VERSION 5.7 ;
BUSBITCHARS "[]" ;
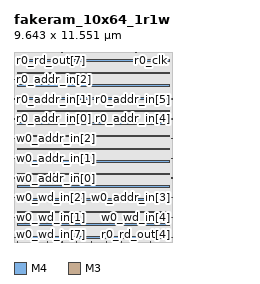
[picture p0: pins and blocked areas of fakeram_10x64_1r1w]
MACRO fakeram_10x64_1r1w
  FOREIGN fakeram_10x64_1r1w 0 0 ;
  SYMMETRY X Y R90 ;
  SIZE 9.643 BY 11.551 ;
  CLASS BLOCK ;
  PIN w0_wd_in[0]
    DIRECTION INPUT ;
    USE SIGNAL ;
    SHAPE ABUTMENT ;
    PORT
      LAYER M4 ;
      RECT 0.000 0.276 0.072 0.300 ;
    END
  END w0_wd_in[0]
  PIN w0_wd_in[1]
    DIRECTION INPUT ;
    USE SIGNAL ;
    SHAPE ABUTMENT ;
    PORT
      LAYER M4 ;
      RECT 0.000 1.476 0.072 1.500 ;
    END
  END w0_wd_in[1]
  PIN w0_wd_in[2]
    DIRECTION INPUT ;
    USE SIGNAL ;
    SHAPE ABUTMENT ;
    PORT
      LAYER M4 ;
      RECT 0.000 2.676 0.072 2.700 ;
    END
  END w0_wd_in[2]
  PIN w0_wd_in[3]
    DIRECTION INPUT ;
    USE SIGNAL ;
    SHAPE ABUTMENT ;
    PORT
      LAYER M4 ;
      RECT 9.571 0.276 9.643 0.300 ;
    END
  END w0_wd_in[3]
  PIN w0_wd_in[4]
    DIRECTION INPUT ;
    USE SIGNAL ;
    SHAPE ABUTMENT ;
    PORT
      LAYER M4 ;
      RECT 9.571 1.476 9.643 1.500 ;
    END
  END w0_wd_in[4]
  PIN w0_wd_in[5]
    DIRECTION OUTPUT ;
    USE SIGNAL ;
    SHAPE ABUTMENT ;
    PORT
      LAYER M3 ;
      RECT 0.207 0.000 0.225 0.054 ;
    END
  END w0_wd_in[5]
  PIN w0_wd_in[6]
    DIRECTION OUTPUT ;
    USE SIGNAL ;
    SHAPE ABUTMENT ;
    PORT
      LAYER M3 ;
      RECT 1.107 0.000 1.125 0.054 ;
    END
  END w0_wd_in[6]
  PIN w0_wd_in[7]
    DIRECTION OUTPUT ;
    USE SIGNAL ;
    SHAPE ABUTMENT ;
    PORT
      LAYER M3 ;
      RECT 2.007 0.000 2.025 0.054 ;
    END
  END w0_wd_in[7]
  PIN w0_wd_in[8]
    DIRECTION OUTPUT ;
    USE SIGNAL ;
    SHAPE ABUTMENT ;
    PORT
      LAYER M3 ;
      RECT 2.907 0.000 2.925 0.054 ;
    END
  END w0_wd_in[8]
  PIN w0_wd_in[9]
    DIRECTION OUTPUT ;
    USE SIGNAL ;
    SHAPE ABUTMENT ;
    PORT
      LAYER M3 ;
      RECT 3.807 0.000 3.825 0.054 ;
    END
  END w0_wd_in[9]
  PIN r0_rd_out[0]
    DIRECTION OUTPUT ;
    USE SIGNAL ;
    SHAPE ABUTMENT ;
    PORT
      LAYER M3 ;
      RECT 4.707 0.000 4.725 0.054 ;
    END
  END r0_rd_out[0]
  PIN r0_rd_out[1]
    DIRECTION OUTPUT ;
    USE SIGNAL ;
    SHAPE ABUTMENT ;
    PORT
      LAYER M3 ;
      RECT 5.607 0.000 5.625 0.054 ;
    END
  END r0_rd_out[1]
  PIN r0_rd_out[2]
    DIRECTION OUTPUT ;
    USE SIGNAL ;
    SHAPE ABUTMENT ;
    PORT
      LAYER M3 ;
      RECT 6.507 0.000 6.525 0.054 ;
    END
  END r0_rd_out[2]
  PIN r0_rd_out[3]
    DIRECTION OUTPUT ;
    USE SIGNAL ;
    SHAPE ABUTMENT ;
    PORT
      LAYER M3 ;
      RECT 7.407 0.000 7.425 0.054 ;
    END
  END r0_rd_out[3]
  PIN r0_rd_out[4]
    DIRECTION OUTPUT ;
    USE SIGNAL ;
    SHAPE ABUTMENT ;
    PORT
      LAYER M3 ;
      RECT 8.307 0.000 8.325 0.054 ;
    END
  END r0_rd_out[4]
  PIN r0_rd_out[5]
    DIRECTION OUTPUT ;
    USE SIGNAL ;
    SHAPE ABUTMENT ;
    PORT
      LAYER M3 ;
      RECT 0.207 11.497 0.225 11.551 ;
    END
  END r0_rd_out[5]
  PIN r0_rd_out[6]
    DIRECTION OUTPUT ;
    USE SIGNAL ;
    SHAPE ABUTMENT ;
    PORT
      LAYER M3 ;
      RECT 1.107 11.497 1.125 11.551 ;
    END
  END r0_rd_out[6]
  PIN r0_rd_out[7]
    DIRECTION OUTPUT ;
    USE SIGNAL ;
    SHAPE ABUTMENT ;
    PORT
      LAYER M3 ;
      RECT 2.007 11.497 2.025 11.551 ;
    END
  END r0_rd_out[7]
  PIN r0_rd_out[8]
    DIRECTION OUTPUT ;
    USE SIGNAL ;
    SHAPE ABUTMENT ;
    PORT
      LAYER M3 ;
      RECT 2.907 11.497 2.925 11.551 ;
    END
  END r0_rd_out[8]
  PIN r0_rd_out[9]
    DIRECTION OUTPUT ;
    USE SIGNAL ;
    SHAPE ABUTMENT ;
    PORT
      LAYER M3 ;
      RECT 3.807 11.497 3.825 11.551 ;
    END
  END r0_rd_out[9]
  PIN w0_addr_in[0]
    DIRECTION INPUT ;
    USE SIGNAL ;
    SHAPE ABUTMENT ;
    PORT
      LAYER M4 ;
      RECT 0.000 3.876 0.072 3.900 ;
    END
  END w0_addr_in[0]
  PIN w0_addr_in[1]
    DIRECTION INPUT ;
    USE SIGNAL ;
    SHAPE ABUTMENT ;
    PORT
      LAYER M4 ;
      RECT 0.000 5.076 0.072 5.100 ;
    END
  END w0_addr_in[1]
  PIN w0_addr_in[2]
    DIRECTION INPUT ;
    USE SIGNAL ;
    SHAPE ABUTMENT ;
    PORT
      LAYER M4 ;
      RECT 0.000 6.276 0.072 6.300 ;
    END
  END w0_addr_in[2]
  PIN w0_addr_in[3]
    DIRECTION INPUT ;
    USE SIGNAL ;
    SHAPE ABUTMENT ;
    PORT
      LAYER M4 ;
      RECT 9.571 2.676 9.643 2.700 ;
    END
  END w0_addr_in[3]
  PIN w0_addr_in[4]
    DIRECTION INPUT ;
    USE SIGNAL ;
    SHAPE ABUTMENT ;
    PORT
      LAYER M4 ;
      RECT 9.571 3.876 9.643 3.900 ;
    END
  END w0_addr_in[4]
  PIN w0_addr_in[5]
    DIRECTION INPUT ;
    USE SIGNAL ;
    SHAPE ABUTMENT ;
    PORT
      LAYER M4 ;
      RECT 9.571 5.076 9.643 5.100 ;
    END
  END w0_addr_in[5]
  PIN r0_addr_in[0]
    DIRECTION INPUT ;
    USE SIGNAL ;
    SHAPE ABUTMENT ;
    PORT
      LAYER M4 ;
      RECT 0.000 7.476 0.072 7.500 ;
    END
  END r0_addr_in[0]
  PIN r0_addr_in[1]
    DIRECTION INPUT ;
    USE SIGNAL ;
    SHAPE ABUTMENT ;
    PORT
      LAYER M4 ;
      RECT 0.000 8.676 0.072 8.700 ;
    END
  END r0_addr_in[1]
  PIN r0_addr_in[2]
    DIRECTION INPUT ;
    USE SIGNAL ;
    SHAPE ABUTMENT ;
    PORT
      LAYER M4 ;
      RECT 0.000 9.876 0.072 9.900 ;
    END
  END r0_addr_in[2]
  PIN r0_addr_in[3]
    DIRECTION INPUT ;
    USE SIGNAL ;
    SHAPE ABUTMENT ;
    PORT
      LAYER M4 ;
      RECT 9.571 6.276 9.643 6.300 ;
    END
  END r0_addr_in[3]
  PIN r0_addr_in[4]
    DIRECTION INPUT ;
    USE SIGNAL ;
    SHAPE ABUTMENT ;
    PORT
      LAYER M4 ;
      RECT 9.571 7.476 9.643 7.500 ;
    END
  END r0_addr_in[4]
  PIN r0_addr_in[5]
    DIRECTION INPUT ;
    USE SIGNAL ;
    SHAPE ABUTMENT ;
    PORT
      LAYER M4 ;
      RECT 9.571 8.676 9.643 8.700 ;
    END
  END r0_addr_in[5]
  PIN w0_we_in
    DIRECTION INPUT ;
    USE SIGNAL ;
    SHAPE ABUTMENT ;
    PORT
      LAYER M3 ;
      RECT 4.707 11.497 4.725 11.551 ;
    END
  END w0_we_in
  PIN w0_ce_in
    DIRECTION INPUT ;
    USE SIGNAL ;
    SHAPE ABUTMENT ;
    PORT
      LAYER M3 ;
      RECT 5.607 11.497 5.625 11.551 ;
    END
  END w0_ce_in
  PIN w0_clk
    DIRECTION INPUT ;
    USE SIGNAL ;
    SHAPE ABUTMENT ;
    PORT
      LAYER M3 ;
      RECT 6.507 11.497 6.525 11.551 ;
    END
  END w0_clk
  PIN r0_ce_in
    DIRECTION INPUT ;
    USE SIGNAL ;
    SHAPE ABUTMENT ;
    PORT
      LAYER M3 ;
      RECT 7.407 11.497 7.425 11.551 ;
    END
  END r0_ce_in
  PIN r0_clk
    DIRECTION INPUT ;
    USE SIGNAL ;
    SHAPE ABUTMENT ;
    PORT
      LAYER M3 ;
      RECT 8.307 11.497 8.325 11.551 ;
    END
  END r0_clk
  PIN VSS
    DIRECTION INOUT ;
    USE GROUND ;
    PORT
      LAYER M4 ;
      RECT 0.216 0.240 9.427 0.336 ;
      RECT 0.216 1.008 9.427 1.104 ;
      RECT 0.216 1.776 9.427 1.872 ;
      RECT 0.216 2.544 9.427 2.640 ;
      RECT 0.216 3.312 9.427 3.408 ;
      RECT 0.216 4.080 9.427 4.176 ;
      RECT 0.216 4.848 9.427 4.944 ;
      RECT 0.216 5.616 9.427 5.712 ;
      RECT 0.216 6.384 9.427 6.480 ;
      RECT 0.216 7.152 9.427 7.248 ;
      RECT 0.216 7.920 9.427 8.016 ;
      RECT 0.216 8.688 9.427 8.784 ;
      RECT 0.216 9.456 9.427 9.552 ;
      RECT 0.216 10.224 9.427 10.320 ;
      RECT 0.216 10.992 9.427 11.088 ;
    END
  END VSS
  PIN VDD
    DIRECTION INOUT ;
    USE POWER ;
    PORT
      LAYER M4 ;
      RECT 0.216 0.240 9.427 0.336 ;
      RECT 0.216 1.008 9.427 1.104 ;
      RECT 0.216 1.776 9.427 1.872 ;
      RECT 0.216 2.544 9.427 2.640 ;
      RECT 0.216 3.312 9.427 3.408 ;
      RECT 0.216 4.080 9.427 4.176 ;
      RECT 0.216 4.848 9.427 4.944 ;
      RECT 0.216 5.616 9.427 5.712 ;
      RECT 0.216 6.384 9.427 6.480 ;
      RECT 0.216 7.152 9.427 7.248 ;
      RECT 0.216 7.920 9.427 8.016 ;
      RECT 0.216 8.688 9.427 8.784 ;
      RECT 0.216 9.456 9.427 9.552 ;
      RECT 0.216 10.224 9.427 10.320 ;
      RECT 0.216 10.992 9.427 11.088 ;
    END
  END VDD
  OBS
    LAYER M1 ;
    RECT 0 0 9.643 11.551 ;
    LAYER M2 ;
    RECT 0 0 9.643 11.551 ;
    LAYER M3 ;
    RECT 0 0 9.643 11.551 ;
    LAYER M4 ;
    RECT 0 0 9.643 11.551 ;
  END
END fakeram_10x64_1r1w

END LIBRARY
